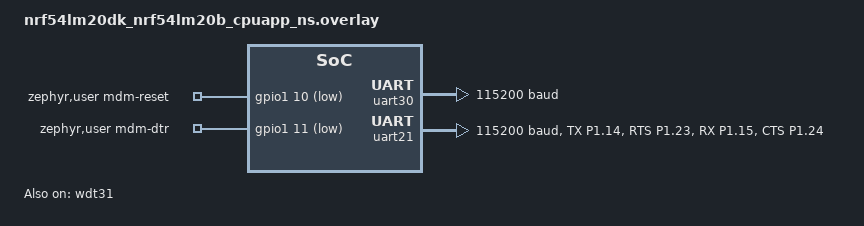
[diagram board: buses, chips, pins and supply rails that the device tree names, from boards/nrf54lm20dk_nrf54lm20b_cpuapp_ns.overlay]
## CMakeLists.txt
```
#
# Copyright (c) 2026 Nordic Semiconductor ASA
#
# SPDX-License-Identifier: LicenseRef-Nordic-5-Clause
#

cmake_minimum_required(VERSION 3.20.0)

find_package(Zephyr REQUIRED HINTS $ENV{ZEPHYR_BASE})
project("Serial Modem Host - 91m1 (AT)")

set(SMHA_LIB_DIR ${CMAKE_CURRENT_SOURCE_DIR}/../../lib)

zephyr_include_directories(
	${SMHA_LIB_DIR}/include
	${CMAKE_CURRENT_SOURCE_DIR}/src
)

target_sources(app PRIVATE
	src/main.c
	src/modem_reset.c
	src/modules/network/network.c
	src/modules/modem_at/modem_at.c
)

target_sources_ifdef(CONFIG_SHELL app PRIVATE src/modules/network/network_shell.c)
target_sources_ifdef(CONFIG_APP_CLOUD app PRIVATE src/modules/cloud/cloud.c)
target_sources_ifdef(CONFIG_APP_LOCATION app PRIVATE src/modules/location/location.c)
target_sources_ifdef(CONFIG_APP_MODEM_POWER app PRIVATE src/modules/modem_power/modem_power.c)
target_sources_ifdef(CONFIG_APP_MODEM_AT_SHELL app PRIVATE src/modules/modem_at/modem_at_shell.c)
target_sources_ifdef(CONFIG_APP_BUTTONS app PRIVATE src/modules/buttons/buttons.c)
target_sources_ifdef(CONFIG_APP_BUTTONS_SHELL app PRIVATE src/modules/buttons/buttons_shell.c)
```

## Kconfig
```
#
# Copyright (c) 2026 Nordic Semiconductor ASA
#
# SPDX-License-Identifier: LicenseRef-Nordic-5-Clause
#

menu "Serial Modem Host 91m1 (AT)"

rsource "src/Kconfig.main"
rsource "src/modules/network/Kconfig.network"
rsource "src/modules/modem_at/Kconfig.modem_at"
rsource "src/modules/modem_power/Kconfig.modem_power"
rsource "src/modules/cloud/Kconfig.cloud"
rsource "src/modules/location/Kconfig.location"
rsource "src/modules/buttons/Kconfig.buttons"

endmenu

menu "Zephyr Kernel"
source "Kconfig.zephyr"
endmenu
```

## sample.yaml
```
sample:
  name: Serial Modem Host 91m1 AT
  description: AT host application for an nRF91 Series Serial Modem.
tests:
  serial_modem_host.applications.91m1_at:
    sysbuild: true
    build_only: true
    integration_platforms:
      - nrf54lm20dk/nrf54lm20b/cpuapp/ns
    platform_allow:
      - nrf54lm20dk/nrf54lm20b/cpuapp/ns
    tags:
      - ci_build
```

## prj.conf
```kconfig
#
# Copyright (c) 2026 Nordic Semiconductor ASA
#
# SPDX-License-Identifier: LicenseRef-Nordic-5-Clause
#

# Application identity
CONFIG_NCS_APPLICATION_BOOT_BANNER_STRING="Serial Modem Host 91m1 (AT)"

# Application modules
CONFIG_APP_NETWORK=y
CONFIG_APP_MODEM_AT=y
CONFIG_APP_MODEM_POWER=y
CONFIG_APP_CLOUD=y
CONFIG_APP_LOCATION=y
CONFIG_APP_BUTTONS=y
CONFIG_APP_MAIN_LOG_LEVEL_DBG=y
CONFIG_APP_NETWORK_LOG_LEVEL_DBG=y
CONFIG_APP_MODEM_AT_LOG_LEVEL_ERR=y
CONFIG_APP_CLOUD_LOG_LEVEL_DBG=y
CONFIG_APP_LOCATION_LOG_LEVEL_DBG=y
CONFIG_APP_BUTTONS_LOG_LEVEL_DBG=y

# System / RTOS
CONFIG_NCS_SAMPLES_DEFAULTS=y
CONFIG_RESET_ON_FATAL_ERROR=n
CONFIG_MAIN_STACK_SIZE=4096
CONFIG_SYSTEM_WORKQUEUE_STACK_SIZE=3072
CONFIG_ZBUS=y
CONFIG_ZBUS_MSG_SUBSCRIBER=y
# Every publish pins one net_buf per message subscriber until that module's thread
# dequeues it, and the pool is shared by all channels. Provisioning holds the cloud
# thread for minutes while LTE goes down and up, so leave room for the queued events.
CONFIG_ZBUS_MSG_SUBSCRIBER_NET_BUF_POOL_SIZE=64
# Name channels and observers so a delivery failure says which ones were involved.
CONFIG_ZBUS_CHANNEL_NAME=y
CONFIG_ZBUS_OBSERVER_NAME=y
CONFIG_SMF=y
CONFIG_SMF_ANCESTOR_SUPPORT=y
CONFIG_SMF_INITIAL_TRANSITION=y
CONFIG_HEAP_MEM_POOL_SIZE=8192

# Watchdog
CONFIG_TASK_WDT=y
CONFIG_WATCHDOG=y
CONFIG_TASK_WDT_MIN_TIMEOUT=10000

# Logging
CONFIG_LOG=y
CONFIG_LOG_MODE_DEFERRED=y
CONFIG_LOG_BUFFER_SIZE=4096

# Shell
CONFIG_SHELL=y
CONFIG_SHELL_STACK_SIZE=4096
# Off so shell wildcard expansion does not mangle `?`/`*` in AT commands.
CONFIG_SHELL_WILDCARD=n

# Serial Modem link: AT commands over UART. The host runs no IP stack; with PPP up,
# the Serial Modem could not use the default PDN for its own nRF Cloud client.
CONFIG_MODEM_MODULES_LOG_LEVEL_INF=y

# Board peripherals
CONFIG_GPIO=y
```

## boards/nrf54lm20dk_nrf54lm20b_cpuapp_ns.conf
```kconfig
#
# Copyright (c) 2026 Nordic Semiconductor ASA
#
# SPDX-License-Identifier: LicenseRef-Nordic-5-Clause
#
# nRF54LM20B DK: console on uart30 (VCOM0), modem on uart21.

CONFIG_UART_ASYNC_API=y
CONFIG_MODEM_BACKEND_UART_ASYNC_HWFC=y

# Shell/console on uart30 uses interrupt-driven UART; modem on uart21 is async-only.
CONFIG_UART_30_INTERRUPT_DRIVEN=y
CONFIG_UART_21_INTERRUPT_DRIVEN=n
CONFIG_UART_21_ASYNC=y

# Default TF-M configuration
CONFIG_TFM_LOG_LEVEL_SILENCE=y
CONFIG_TFM_SFN=y
CONFIG_TFM_IPC=n
CONFIG_TFM_PSA_FRAMEWORK_HAS_MM_IOVEC=y
CONFIG_TFM_ITS_ENCRYPTED=n
```

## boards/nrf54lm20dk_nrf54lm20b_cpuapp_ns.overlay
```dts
/*
 * Copyright (c) 2026 Nordic Semiconductor ASA
 *
 * SPDX-License-Identifier: LicenseRef-Nordic-5-Clause
 *
 * nRF54LM20B DK + nRF9151 DK.
 *
 * Console uses uart30 (VCOM0).
 *
 * The Serial Modem link uses uart21 on P1.14–P1.15 (TX/RX, P2 connector) and
 * P1.23–P1.24 (RTS/CTS, P3 connector). DTR/reset use P1.11/P1.10 (P2
 * connector). RI (P1.12) is wired but unused, as DTR stays asserted.
 *
 * Application button 1 is BUTTON0 and button 2 is BUTTON1. BUTTON3 is removed,
 * as it is the only button on gpio0. The DK library adds one GPIO callback to
 * every port that has a button, and linking it into both port lists drops the
 * other gpio1 callbacks.
 *
 * Set matching VDD on both DKs (typically 1.8 V).
 *
 * Wiring: see docs/getting-started/ppp-nrf54.md.
 */

/ {
	aliases {
		/delete-property/ sw3;
	};

	chosen {
		zephyr,console = &uart30;
		zephyr,shell-uart = &uart30;
	};

	/* Serial Modem link. The application drives the modem with AT commands over
	 * modem-uart, holds DTR asserted to keep the Serial Modem UART enabled, and
	 * pulses nRESET at boot.
	 */
	zephyr,user {
		modem-uart = <&uart21>;
		mdm-reset-gpios = <&gpio1 10 (GPIO_ACTIVE_LOW | GPIO_OPEN_DRAIN)>;
		mdm-dtr-gpios = <&gpio1 11 GPIO_ACTIVE_LOW>;
	};
};

/delete-node/ &button3;

&uart30 {
	status = "okay";
	current-speed = <115200>;
};

&pinctrl {
	uart21_default: uart21_default {
		group1 {
			psels = <NRF_PSEL(UART_TX, 1, 14)>,
				<NRF_PSEL(UART_RTS, 1, 23)>;
		};

		group2 {
			psels = <NRF_PSEL(UART_RX, 1, 15)>,
				<NRF_PSEL(UART_CTS, 1, 24)>;
			bias-pull-up;
		};
	};

	uart21_sleep: uart21_sleep {
		group1 {
			psels = <NRF_PSEL(UART_TX, 1, 14)>,
				<NRF_PSEL(UART_RX, 1, 15)>,
				<NRF_PSEL(UART_RTS, 1, 23)>,
				<NRF_PSEL(UART_CTS, 1, 24)>;
			low-power-enable;
		};
	};
};

&uart21 {
	status = "okay";
	current-speed = <115200>;
	pinctrl-0 = <&uart21_default>;
	pinctrl-1 = <&uart21_sleep>;
	pinctrl-names = "default", "sleep";
	hw-flow-control;
};

&gpio1 {
	status = "okay";
};

/* Non-secure hardware watchdog, fallback for CONFIG_TASK_WDT_HW_FALLBACK. */
&wdt31 {
	status = "okay";
};
```

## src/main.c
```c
/*
 * Copyright (c) 2026 Nordic Semiconductor ASA
 *
 * SPDX-License-Identifier: LicenseRef-Nordic-5-Clause
 */

#include <zephyr/kernel.h>
#include <zephyr/logging/log.h>
#include <zephyr/zbus/zbus.h>
#include <zephyr/task_wdt/task_wdt.h>
#include <zephyr/smf.h>

#include "app_common.h"
#include "modules/network/network.h"
#include "modules/cloud/cloud.h"

#if defined(CONFIG_APP_LOCATION)
#include "modules/location/location.h"
#endif /* CONFIG_APP_LOCATION */

#if defined(CONFIG_APP_BUTTONS)
#include "modules/buttons/buttons.h"
#endif /* CONFIG_APP_BUTTONS */

LOG_MODULE_REGISTER(main, CONFIG_APP_MAIN_LOG_LEVEL);

BUILD_ASSERT(CONFIG_APP_MAIN_WATCHDOG_TIMEOUT_SECONDS >
	     CONFIG_APP_MAIN_MSG_PROCESSING_TIMEOUT_SECONDS,
	     "Watchdog timeout must exceed the maximum message processing time");

#if defined(CONFIG_APP_LOCATION)
#define HAS_SYNC_STEPS 1
#endif

ZBUS_MSG_SUBSCRIBER_DEFINE(main_subscriber);

/* Private channel message types for internal state management. */
enum priv_main_msg_type {
	MAIN_PRIV_SYNC,
};

struct priv_main_msg {
	enum priv_main_msg_type type;
};

ZBUS_CHAN_DEFINE(main_priv_chan,
		 struct priv_main_msg,
		 NULL,
		 NULL,
		 ZBUS_OBSERVERS_EMPTY,
		 ZBUS_MSG_INIT(0)
);

#define CHANNEL_LIST(X) \
	X(main_priv_chan, struct priv_main_msg) \
	X(network_chan, struct network_msg) \
	X(cloud_chan, struct cloud_msg) \
	IF_ENABLED(CONFIG_APP_LOCATION, (X(location_chan, struct location_msg))) \
	IF_ENABLED(CONFIG_APP_BUTTONS, (X(button_chan, struct button_msg)))

#define MAX_MSG_SIZE MAX_MSG_SIZE_FROM_LIST(CHANNEL_LIST)

#define ADD_OBSERVERS(_chan, _type) ZBUS_CHAN_ADD_OBS(_chan, main_subscriber, 0);
CHANNEL_LIST(ADD_OBSERVERS)

/** Application SMF states. */
enum main_app_state {
	/**
	 * Top-level state. Relays the network state to the cloud module and consumes the
	 * messages that no substate acts on. The initial substate is
	 * @ref STATE_CLOUD_DISCONNECTED.
	 */
	STATE_RUNNING,
		/**
		 * The Serial Modem nRF Cloud client is not connected. Synchronization is
		 * not scheduled, and synchronization triggers are ignored.
		 */
		STATE_CLOUD_DISCONNECTED,
		/**
		 * The Serial Modem nRF Cloud client is connected. The first synchronization
		 * runs after CONFIG_APP_SYNC_BOOT_DELAY_SECONDS, then every
		 * CONFIG_APP_SYNC_INTERVAL.
		 *
		 * The initial substate is @ref STATE_SYNC_IDLE. Each synchronization
		 * advances through the sync substates in order, waiting for each step
		 * to complete before starting the next.
		 */
		STATE_CLOUD_CONNECTED,
			/** Waiting for the next synchronization trigger. */
			STATE_SYNC_IDLE,
#if defined(HAS_SYNC_STEPS)
			/**
			 * A synchronization is running. Triggers are ignored until it
			 * returns to @ref STATE_SYNC_IDLE. The initial substate is the
			 * first enabled sync step.
			 */
			STATE_SYNCING,
#endif /* HAS_SYNC_STEPS */
#if defined(CONFIG_APP_LOCATION)
				/** Requesting a location fix through the Serial Modem. */
				STATE_SYNC_LOCATION,
#endif /* CONFIG_APP_LOCATION */
};

#if defined(HAS_SYNC_STEPS)
#define STATE_SYNC_FIRST_STEP STATE_SYNC_LOCATION
#endif /* HAS_SYNC_STEPS */

/* State object for the main module. */
struct main_state {
	struct smf_ctx ctx;
	const struct zbus_channel *chan;
	uint8_t msg_buf[MAX_MSG_SIZE];
};

static struct main_state main_state;
static const struct smf_state states[];

static void sync_work_handler(struct k_work *work);
static K_WORK_DELAYABLE_DEFINE(sync_work, sync_work_handler);

/** Forward declarations */

static void state_running_entry(void *obj);
static enum smf_state_result state_running_run(void *obj);
static void state_cloud_disconnected_entry(void *obj);
static enum smf_state_result state_cloud_disconnected_run(void *obj);
static void state_cloud_connected_entry(void *obj);
static enum smf_state_result state_cloud_connected_run(void *obj);
static void state_cloud_connected_exit(void *obj);
static enum smf_state_result state_sync_idle_run(void *obj);

#if defined(HAS_SYNC_STEPS)
static void state_syncing_entry(void *obj);
static enum smf_state_result state_syncing_run(void *obj);
#endif /* HAS_SYNC_STEPS */

#if defined(CONFIG_APP_LOCATION)
static void state_sync_location_entry(void *obj);
static enum smf_state_result state_sync_location_run(void *obj);
#endif /* CONFIG_APP_LOCATION */

/** SMF state table */
static const struct smf_state states[] = {
	[STATE_RUNNING] =
		SMF_CREATE_STATE(state_running_entry,
				 state_running_run,
				 NULL,
				 NULL,
				 &states[STATE_CLOUD_DISCONNECTED]),
	[STATE_CLOUD_DISCONNECTED] =
		SMF_CREATE_STATE(state_cloud_disconnected_entry,
				 state_cloud_disconnected_run,
				 NULL,
				 &states[STATE_RUNNING],
				 NULL),
	[STATE_CLOUD_CONNECTED] =
		SMF_CREATE_STATE(state_cloud_connected_entry,
				 state_cloud_connected_run,
				 state_cloud_connected_exit,
				 &states[STATE_RUNNING],
				 &states[STATE_SYNC_IDLE]),
	[STATE_SYNC_IDLE] =
		SMF_CREATE_STATE(NULL,
				 state_sync_idle_run,
				 NULL,
				 &states[STATE_CLOUD_CONNECTED],
				 NULL),
#if defined(HAS_SYNC_STEPS)
	[STATE_SYNCING] =
		SMF_CREATE_STATE(state_syncing_entry,
				 state_syncing_run,
				 NULL,
				 &states[STATE_CLOUD_CONNECTED],
				 &states[STATE_SYNC_FIRST_STEP]),
#endif /* HAS_SYNC_STEPS */
#if defined(CONFIG_APP_LOCATION)
	[STATE_SYNC_LOCATION] =
		SMF_CREATE_STATE(state_sync_location_entry,
				 state_sync_location_run,
				 NULL,
				 &states[STATE_SYNCING],
				 NULL),
#endif /* CONFIG_APP_LOCATION */
};

/** Convenience functions */

static void sync_schedule(k_timeout_t delay)
{
	int err;

	err = k_work_reschedule(&sync_work, delay);
	if (err < 0) {
		LOG_ERR("k_work_reschedule sync_work, error: %d", err);
		FATAL_ERROR();
	}
}

static void sync_cancel(void)
{
	(void)k_work_cancel_delayable(&sync_work);
}

/* Publishes a sync trigger and schedules the next one, so the interval is kept even when a
 * trigger arrives while a synchronization is running and is ignored.
 */
static void sync_work_handler(struct k_work *work)
{
	ARG_UNUSED(work);

	struct priv_main_msg msg = { .type = MAIN_PRIV_SYNC };
	int err;

	err = zbus_chan_pub(&main_priv_chan, &msg, PUB_TIMEOUT);
	if (err) {
		LOG_ERR("zbus_chan_pub main_priv_chan, error: %d", err);
		FATAL_ERROR();
	}

	sync_schedule(K_SECONDS(CONFIG_APP_SYNC_INTERVAL));
}

static void cloud_request(enum cloud_msg_type type)
{
	struct cloud_msg msg = { .type = type };
	int err;

	err = zbus_chan_pub(&cloud_chan, &msg, PUB_TIMEOUT);
	if (err) {
		LOG_ERR("zbus_chan_pub cloud_chan, error: %d", err);
		FATAL_ERROR();
	}
}

#if defined(CONFIG_APP_LOCATION)
static void location_fix_request(void)
{
	struct location_msg msg = { .type = LOCATION_FIX_REQUEST };
	int err;

	err = zbus_chan_pub(&location_chan, &msg, PUB_TIMEOUT);
	if (err) {
		LOG_ERR("zbus_chan_pub location_chan, error: %d", err);
		FATAL_ERROR();
	}
}
#endif /* CONFIG_APP_LOCATION */

#if defined(CONFIG_APP_BUTTONS)
/* Returns true if the message on button_chan is a Button 1 press, the sync trigger. */
static bool is_sync_button(const struct main_state *state_object)
{
	const struct button_msg *msg = (const struct button_msg *)state_object->msg_buf;

	return state_object->chan == &button_chan && msg->type == BUTTON_1;
}
#endif /* CONFIG_APP_BUTTONS */

/** SMF state functions */

static void state_running_entry(void *obj)
{
	ARG_UNUSED(obj);

	LOG_INF("state_running_entry");
}

static enum smf_state_result state_running_run(void *obj)
{
	struct main_state *state_object = obj;

	if (state_object->chan == &network_chan) {
		const struct network_msg *msg = (const struct network_msg *)state_object->msg_buf;

		if (msg->type == NETWORK_CONNECTED) {
			LOG_DBG("Network connected, requesting cloud connection");
			cloud_request(CLOUD_CONNECT);
		} else if (msg->type == NETWORK_DISCONNECTED) {
			LOG_DBG("Network disconnected, releasing cloud connection");
			cloud_request(CLOUD_DISCONNECT);
		} else {
		}

		return SMF_EVENT_HANDLED;
	}

#if defined(CONFIG_APP_BUTTONS)
	if (state_object->chan == &button_chan) {
		const struct button_msg *msg = (const struct button_msg *)state_object->msg_buf;

		LOG_WRN("Button %u: no action defined", msg->type);

		return SMF_EVENT_HANDLED;
	}
#endif /* CONFIG_APP_BUTTONS */

	/* Requests echoed back on module channels, completions that arrive after the cloud
	 * disconnected, and cloud state reports that do not change the state are consumed here.
	 */
	return SMF_EVENT_HANDLED;
}

static void state_cloud_disconnected_entry(void *obj)
{
	ARG_UNUSED(obj);

	LOG_INF("state_cloud_disconnected_entry");
	LOG_INF("Cloud disconnected");
}

static enum smf_state_result state_cloud_disconnected_run(void *obj)
{
	struct main_state *state_object = obj;

	if (state_object->chan == &cloud_chan) {
		const struct cloud_msg *msg = (const struct cloud_msg *)state_object->msg_buf;

		if (msg->type == CLOUD_CONNECTED) {
			smf_set_state(SMF_CTX(state_object), &states[STATE_CLOUD_CONNECTED]);

			return SMF_EVENT_HANDLED;
		}
	}

#if defined(CONFIG_APP_BUTTONS)
	if (is_sync_button(state_object)) {
		LOG_INF("Button 1: cloud is disconnected, sync skipped");

		return SMF_EVENT_HANDLED;
	}
#endif /* CONFIG_APP_BUTTONS */

	return SMF_EVENT_PROPAGATE;
}

static void state_cloud_connected_entry(void *obj)
{
	ARG_UNUSED(obj);

	LOG_INF("state_cloud_connected_entry");
	LOG_INF("Cloud connected, first sync in %d s", CONFIG_APP_SYNC_BOOT_DELAY_SECONDS);

	sync_schedule(K_SECONDS(CONFIG_APP_SYNC_BOOT_DELAY_SECONDS));
}

static enum smf_state_result state_cloud_connected_run(void *obj)
{
	struct main_state *state_object = obj;

	if (state_object->chan == &cloud_chan) {
		const struct cloud_msg *msg = (const struct cloud_msg *)state_object->msg_buf;

		if (msg->type == CLOUD_DISCONNECTED) {
			smf_set_state(SMF_CTX(state_object), &states[STATE_CLOUD_DISCONNECTED]);

			return SMF_EVENT_HANDLED;
		}
	}

	return SMF_EVENT_PROPAGATE;
}

static void state_cloud_connected_exit(void *obj)
{
	ARG_UNUSED(obj);

	LOG_INF("state_cloud_connected_exit");

	sync_cancel();
}

static enum smf_state_result state_sync_idle_run(void *obj)
{
	struct main_state *state_object = obj;

	if (state_object->chan == &main_priv_chan) {
		const struct priv_main_msg *msg =
			(const struct priv_main_msg *)state_object->msg_buf;

		if (msg->type == MAIN_PRIV_SYNC) {
			LOG_DBG("Sync tick, next in %d s", CONFIG_APP_SYNC_INTERVAL);
#if defined(HAS_SYNC_STEPS)
			smf_set_state(SMF_CTX(state_object), &states[STATE_SYNCING]);
#endif /* HAS_SYNC_STEPS */

			return SMF_EVENT_HANDLED;
		}
	}

#if defined(CONFIG_APP_BUTTONS)
	if (is_sync_button(state_object)) {
		LOG_INF("Button 1: sync requested");
		sync_schedule(K_NO_WAIT);

		return SMF_EVENT_HANDLED;
	}
#endif /* CONFIG_APP_BUTTONS */

	return SMF_EVENT_PROPAGATE;
}

#if defined(HAS_SYNC_STEPS)
static void state_syncing_entry(void *obj)
{
	ARG_UNUSED(obj);

	LOG_DBG("state_syncing_entry");
}

static enum smf_state_result state_syncing_run(void *obj)
{
	struct main_state *state_object = obj;

	if (state_object->chan == &main_priv_chan) {
		LOG_WRN("Sync requested while a sync is running, ignoring");

		return SMF_EVENT_HANDLED;
	}

#if defined(CONFIG_APP_BUTTONS)
	if (is_sync_button(state_object)) {
		LOG_INF("Button 1: sync is running, sync skipped");

		return SMF_EVENT_HANDLED;
	}
#endif /* CONFIG_APP_BUTTONS */

	return SMF_EVENT_PROPAGATE;
}
#endif /* HAS_SYNC_STEPS */

#if defined(CONFIG_APP_LOCATION)
static void state_sync_location_entry(void *obj)
{
	ARG_UNUSED(obj);

	LOG_DBG("state_sync_location_entry");

	location_fix_request();
}

static enum smf_state_result state_sync_location_run(void *obj)
{
	struct main_state *state_object = obj;

	if (state_object->chan == &location_chan) {
		const struct location_msg *msg =
			(const struct location_msg *)state_object->msg_buf;

		if (msg->type == LOCATION_FIX_DONE) {
			smf_set_state(SMF_CTX(state_object), &states[STATE_SYNC_IDLE]);

			return SMF_EVENT_HANDLED;
		}
	}

	return SMF_EVENT_PROPAGATE;
}
#endif /* CONFIG_APP_LOCATION */

static void main_wdt_callback(int channel_id, void *user_data)
{
	LOG_ERR("Main watchdog expired, channel: %d, thread: %s",
		channel_id, k_thread_name_get((k_tid_t)user_data));

	FATAL_ERROR_WATCHDOG_TIMEOUT();
}

int main(void)
{
	int err;
	int task_wdt_id;
	const uint32_t wdt_timeout_ms =
		(CONFIG_APP_MAIN_WATCHDOG_TIMEOUT_SECONDS * MSEC_PER_SEC);
	const uint32_t execution_time_ms =
		(CONFIG_APP_MAIN_MSG_PROCESSING_TIMEOUT_SECONDS * MSEC_PER_SEC);
	const k_timeout_t zbus_wait = K_MSEC(wdt_timeout_ms - execution_time_ms);

	err = task_wdt_init(DEVICE_DT_GET(DT_ALIAS(watchdog0)));
	if (err) {
		LOG_ERR("task_wdt_init, error: %d", err);
		FATAL_ERROR();
		return -EFAULT;
	}

	task_wdt_id = task_wdt_add(wdt_timeout_ms, main_wdt_callback, (void *)k_current_get());
	if (task_wdt_id < 0) {
		LOG_ERR("task_wdt_add, error: %d", task_wdt_id);
		FATAL_ERROR();
		return -EFAULT;
	}

	smf_set_initial(SMF_CTX(&main_state), &states[STATE_RUNNING]);

	while (true) {
		err = task_wdt_feed(task_wdt_id);
		if (err) {
			LOG_ERR("task_wdt_feed, error: %d", err);
			FATAL_ERROR();
			return -EFAULT;
		}

		err = zbus_sub_wait_msg(&main_subscriber, &main_state.chan,
					main_state.msg_buf, zbus_wait);
		if (err == -ENOMSG) {
			continue;
		} else if (err) {
			LOG_ERR("zbus_sub_wait_msg, error: %d", err);
			FATAL_ERROR();
			return -EFAULT;
		}

		err = smf_run_state(SMF_CTX(&main_state));
		if (err) {
			LOG_ERR("smf_run_state, error: %d", err);
			FATAL_ERROR();
			return -EFAULT;
		}
	}

	return 0;
}
```

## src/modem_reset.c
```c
/*
 * Copyright (c) 2026 Nordic Semiconductor ASA
 *
 * SPDX-License-Identifier: LicenseRef-Nordic-5-Clause
 */

#include <zephyr/devicetree.h>
#include <zephyr/drivers/gpio.h>
#include <zephyr/init.h>
#include <zephyr/kernel.h>

#include "app_common.h"

#define MODEM_NODE DT_PATH(zephyr_user)

#if DT_NODE_HAS_PROP(MODEM_NODE, mdm_reset_gpios)

#define MODEM_RESET_PULSE_MS 500
#define MODEM_STARTUP_TIME_MS 2000

static int modem_reset_on_host_boot(void)
{
	const struct gpio_dt_spec reset = GPIO_DT_SPEC_GET(MODEM_NODE, mdm_reset_gpios);
	int err;

	if (!gpio_is_ready_dt(&reset)) {
		FATAL_ERROR();
		return -ENODEV;
	}

	err = gpio_pin_configure_dt(&reset, GPIO_OUTPUT_INACTIVE);
	if (err != 0) {
		FATAL_ERROR();
		return err;
	}

	gpio_pin_set_dt(&reset, 1);
	k_msleep(MODEM_RESET_PULSE_MS);
	gpio_pin_set_dt(&reset, 0);
	k_msleep(MODEM_STARTUP_TIME_MS);

	return 0;
}

SYS_INIT(modem_reset_on_host_boot, POST_KERNEL, 50);

#endif
```
